VERSION 5.8 ;
BUSBITCHARS "[]" ;
DIVIDERCHAR "/" ;
UNITS
    DATABASE MICRONS 1000 ;
END UNITS

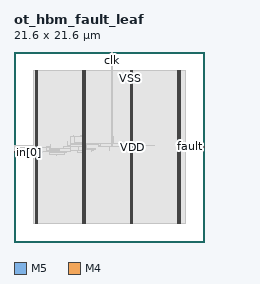
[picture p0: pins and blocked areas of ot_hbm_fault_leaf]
MACRO ot_hbm_fault_leaf
  FOREIGN ot_hbm_fault_leaf 0 0 ;
  CLASS BLOCK ;
  SIZE 21.6 BY 21.6 ;
  PIN clk
    DIRECTION INPUT ;
    USE SIGNAL ;
    PORT
      LAYER M5 ;
        RECT  11.088 21.516 11.112 21.6 ;
    END
  END clk
  PIN fault
    DIRECTION OUTPUT ;
    USE SIGNAL ;
    PORT
      LAYER M4 ;
        RECT  21.516 10.8 21.6 10.824 ;
    END
  END fault
  PIN in[0]
    DIRECTION INPUT ;
    USE SIGNAL ;
    PORT
      LAYER M4 ;
        RECT  0 10.128 0.084 10.152 ;
    END
  END in[0]
  PIN in[1]
    DIRECTION INPUT ;
    USE SIGNAL ;
    PORT
      LAYER M4 ;
        RECT  0 10.224 0.084 10.248 ;
    END
  END in[1]
  PIN in[2]
    DIRECTION INPUT ;
    USE SIGNAL ;
    PORT
      LAYER M4 ;
        RECT  0 10.32 0.084 10.344 ;
    END
  END in[2]
  PIN in[3]
    DIRECTION INPUT ;
    USE SIGNAL ;
    PORT
      LAYER M4 ;
        RECT  0 10.416 0.084 10.44 ;
    END
  END in[3]
  PIN in[4]
    DIRECTION INPUT ;
    USE SIGNAL ;
    PORT
      LAYER M4 ;
        RECT  0 10.512 0.084 10.536 ;
    END
  END in[4]
  PIN in[5]
    DIRECTION INPUT ;
    USE SIGNAL ;
    PORT
      LAYER M4 ;
        RECT  0 10.608 0.084 10.632 ;
    END
  END in[5]
  PIN in[6]
    DIRECTION INPUT ;
    USE SIGNAL ;
    PORT
      LAYER M4 ;
        RECT  0 10.704 0.084 10.728 ;
    END
  END in[6]
  PIN rst_n
    DIRECTION INPUT ;
    USE SIGNAL ;
    PORT
      LAYER M5 ;
        RECT  11.184 21.516 11.208 21.6 ;
    END
  END rst_n
  PIN VDD
    DIRECTION INOUT ;
    USE POWER ;
    PORT
      LAYER M5 ;
        RECT  18.792 2.151 18.912 19.449 ;
        RECT  13.392 2.151 13.512 19.449 ;
        RECT  7.992 2.151 8.112 19.449 ;
        RECT  2.592 2.151 2.712 19.449 ;
    END
  END VDD
  PIN VSS
    DIRECTION INOUT ;
    USE GROUND ;
    PORT
      LAYER M5 ;
        RECT  18.6 2.137 18.72 19.463 ;
        RECT  13.2 2.137 13.32 19.463 ;
        RECT  7.8 2.137 7.92 19.463 ;
        RECT  2.4 2.137 2.52 19.463 ;
    END
  END VSS
  OBS
    LAYER RVTN ;
     RECT  2.16 2.16 19.44 2.295 ;
     RECT  2.16 2.565 19.44 2.835 ;
     RECT  2.16 3.105 19.44 3.375 ;
     RECT  2.16 3.645 19.44 3.915 ;
     RECT  2.16 4.185 19.44 4.455 ;
     RECT  2.16 4.725 19.44 4.995 ;
     RECT  2.16 5.265 19.44 5.535 ;
     RECT  2.16 5.805 19.44 6.075 ;
     RECT  2.16 6.345 19.44 6.615 ;
     RECT  2.16 6.885 19.44 7.155 ;
     RECT  2.16 7.425 19.44 7.695 ;
     RECT  2.16 7.965 19.44 8.235 ;
     RECT  2.16 8.505 19.44 8.775 ;
     RECT  2.16 9.045 19.44 9.315 ;
     RECT  2.16 9.585 19.44 9.855 ;
     RECT  2.16 10.125 19.44 10.395 ;
     RECT  2.16 10.665 19.44 10.935 ;
     RECT  2.16 11.205 19.44 11.475 ;
     RECT  2.16 11.745 19.44 12.015 ;
     RECT  2.16 12.285 19.44 12.555 ;
     RECT  2.16 12.825 19.44 13.095 ;
     RECT  2.16 13.365 19.44 13.635 ;
     RECT  2.16 13.905 19.44 14.175 ;
     RECT  2.16 14.445 19.44 14.715 ;
     RECT  2.16 14.985 19.44 15.255 ;
     RECT  2.16 15.525 19.44 15.795 ;
     RECT  2.16 16.065 19.44 16.335 ;
     RECT  2.16 16.605 19.44 16.875 ;
     RECT  2.16 17.145 19.44 17.415 ;
     RECT  2.16 17.685 19.44 17.955 ;
     RECT  2.16 18.225 19.44 18.495 ;
     RECT  2.16 18.765 19.44 19.035 ;
     RECT  2.16 19.305 19.44 19.44 ;
    LAYER RVTP ;
     RECT  2.16 2.295 19.44 2.565 ;
     RECT  2.16 2.835 19.44 3.105 ;
     RECT  2.16 3.375 19.44 3.645 ;
     RECT  2.16 3.915 19.44 4.185 ;
     RECT  2.16 4.455 19.44 4.725 ;
     RECT  2.16 4.995 19.44 5.265 ;
     RECT  2.16 5.535 19.44 5.805 ;
     RECT  2.16 6.075 19.44 6.345 ;
     RECT  2.16 6.615 19.44 6.885 ;
     RECT  2.16 7.155 19.44 7.425 ;
     RECT  2.16 7.695 19.44 7.965 ;
     RECT  2.16 8.235 19.44 8.505 ;
     RECT  2.16 8.775 19.44 9.045 ;
     RECT  2.16 9.315 19.44 9.585 ;
     RECT  2.16 9.855 19.44 10.125 ;
     RECT  2.16 10.395 19.44 10.665 ;
     RECT  2.16 10.935 19.44 11.205 ;
     RECT  2.16 11.475 19.44 11.745 ;
     RECT  2.16 12.015 19.44 12.285 ;
     RECT  2.16 12.555 19.44 12.825 ;
     RECT  2.16 13.095 19.44 13.365 ;
     RECT  2.16 13.635 19.44 13.905 ;
     RECT  2.16 14.175 19.44 14.445 ;
     RECT  2.16 14.715 19.44 14.985 ;
     RECT  2.16 15.255 19.44 15.525 ;
     RECT  2.16 15.795 19.44 16.065 ;
     RECT  2.16 16.335 19.44 16.605 ;
     RECT  2.16 16.875 19.44 17.145 ;
     RECT  2.16 17.415 19.44 17.685 ;
     RECT  2.16 17.955 19.44 18.225 ;
     RECT  2.16 18.495 19.44 18.765 ;
     RECT  2.16 19.035 19.44 19.305 ;
    LAYER M1 ;
     RECT  2.16 2.151 19.44 19.449 ;
    LAYER M2 ;
     RECT  0.103 10.98 2.16 10.998 ;
     RECT  2.16 2.151 19.44 19.449 ;
     RECT  19.44 10.836 20.507 10.854 ;
    LAYER M3 ;
     RECT  2.415 2.143 2.505 2.413 ;
     RECT  7.815 2.143 7.905 2.413 ;
     RECT  13.215 2.143 13.305 2.413 ;
     RECT  18.615 2.143 18.705 2.413 ;
     RECT  2.415 2.413 2.697 9.859 ;
     RECT  4.824 9.859 4.842 9.895 ;
     RECT  4.824 9.895 5.49 9.931 ;
     RECT  2.415 9.859 2.862 10.093 ;
     RECT  2.268 10.093 2.862 10.129 ;
     RECT  7.815 2.413 8.097 10.165 ;
     RECT  4.068 9.931 5.742 10.201 ;
     RECT  2.268 10.129 3.222 10.253 ;
     RECT  4.068 10.201 5.958 10.267 ;
     RECT  8.82 10.327 8.838 10.399 ;
     RECT  4.068 10.267 6.426 10.459 ;
     RECT  7.272 10.165 8.097 10.459 ;
     RECT  4.068 10.459 8.097 10.471 ;
     RECT  8.82 10.399 8.982 10.471 ;
     RECT  4.068 10.471 9.306 10.589 ;
     RECT  2.304 10.253 3.222 10.625 ;
     RECT  5.22 10.589 9.306 10.625 ;
     RECT  5.22 10.625 8.226 10.661 ;
     RECT  8.964 10.625 9.306 10.661 ;
     RECT  0.324 10.603 0.342 10.699 ;
     RECT  4.068 10.589 4.194 10.699 ;
     RECT  0.108 10.699 0.342 10.733 ;
     RECT  20.484 10.795 20.502 10.859 ;
     RECT  3.708 10.699 4.194 10.895 ;
     RECT  5.652 10.661 8.226 10.895 ;
     RECT  10.836 10.399 10.854 10.939 ;
     RECT  12.024 10.843 12.042 10.939 ;
     RECT  10.836 10.939 12.042 10.967 ;
     RECT  9.576 10.843 9.918 10.976 ;
     RECT  11.34 10.967 12.042 10.987 ;
     RECT  0.108 10.733 0.126 11.003 ;
     RECT  6.12 10.895 8.226 11.021 ;
     RECT  15.912 10.975 15.93 11.021 ;
     RECT  9.9 10.976 9.918 11.035 ;
     RECT  4.176 10.895 4.194 11.039 ;
     RECT  6.876 11.021 8.226 11.129 ;
     RECT  9.9 11.035 10.026 11.165 ;
     RECT  11.34 10.987 12.33 11.165 ;
     RECT  6.876 11.129 8.154 11.273 ;
     RECT  6.12 11.021 6.138 11.399 ;
     RECT  12.312 11.165 12.33 11.399 ;
     RECT  11.34 11.165 11.358 11.939 ;
     RECT  11.16 11.947 11.178 11.984 ;
     RECT  6.876 11.273 8.097 11.995 ;
     RECT  6.732 11.995 8.097 12.047 ;
     RECT  6.732 12.047 6.75 12.083 ;
     RECT  7.524 12.047 8.097 12.083 ;
     RECT  2.415 10.625 2.697 19.187 ;
     RECT  7.815 12.083 8.097 19.187 ;
     RECT  13.215 2.413 13.497 19.187 ;
     RECT  18.615 2.413 18.897 19.187 ;
     RECT  2.415 19.187 2.505 19.457 ;
     RECT  7.815 19.187 7.905 19.457 ;
     RECT  13.215 19.187 13.305 19.457 ;
     RECT  18.615 19.187 18.705 19.457 ;
    LAYER M4 ;
     RECT  0.06 10.128 2.408 10.728 ;
     RECT  2.408 2.148 2.512 19.452 ;
     RECT  2.512 2.418 2.704 19.182 ;
     RECT  2.704 10.272 3.737 10.728 ;
     RECT  3.737 10.272 5.209 10.44 ;
     RECT  5.209 10.272 6.397 10.584 ;
     RECT  6.397 10.272 6.437 11.016 ;
     RECT  6.421 12 6.761 12.024 ;
     RECT  6.437 10.416 7.381 11.016 ;
     RECT  7.381 10.416 7.808 11.16 ;
     RECT  7.808 2.148 7.912 19.452 ;
     RECT  7.912 2.418 8.104 19.182 ;
     RECT  8.104 10.848 8.243 11.16 ;
     RECT  8.243 11.04 9.565 11.16 ;
     RECT  9.565 10.944 9.889 11.16 ;
     RECT  9.889 10.848 11.149 11.16 ;
     RECT  11.149 10.848 11.233 11.976 ;
     RECT  11.233 10.848 12.053 11.16 ;
     RECT  12.053 10.992 13.208 11.16 ;
     RECT  13.208 2.148 13.312 19.452 ;
     RECT  13.312 2.418 13.504 19.182 ;
     RECT  13.504 10.992 15.941 11.016 ;
     RECT  18.608 2.148 18.712 19.452 ;
     RECT  18.712 2.418 18.904 19.182 ;
     RECT  20.473 10.8 21.564 10.824 ;
    LAYER M5 ;
     RECT  2.4 2.137 2.52 2.151 ;
     RECT  7.8 2.137 7.92 2.151 ;
     RECT  13.2 2.137 13.32 2.151 ;
     RECT  18.6 2.137 18.72 2.151 ;
     RECT  6.432 10.453 6.456 10.837 ;
     RECT  7.8 2.151 8.112 10.837 ;
     RECT  6.432 10.837 8.232 11.075 ;
     RECT  6.432 11.075 8.112 11.171 ;
     RECT  11.088 10.933 11.112 11.941 ;
     RECT  6.432 11.171 6.456 12.035 ;
     RECT  2.4 2.151 2.712 19.449 ;
     RECT  7.8 11.171 8.112 19.449 ;
     RECT  13.2 2.151 13.512 19.449 ;
     RECT  18.6 2.151 18.912 19.449 ;
     RECT  2.4 19.449 2.52 19.463 ;
     RECT  7.8 19.449 7.92 19.463 ;
     RECT  13.2 19.449 13.32 19.463 ;
     RECT  18.6 19.449 18.72 19.463 ;
     RECT  11.088 11.941 11.208 21.584 ;
  END
END ot_hbm_fault_leaf
END LIBRARY
